One B-rep face of a CAD part: STEP entity #1865.
In plain terms, the planar face has unit normal (1, 0, 0).
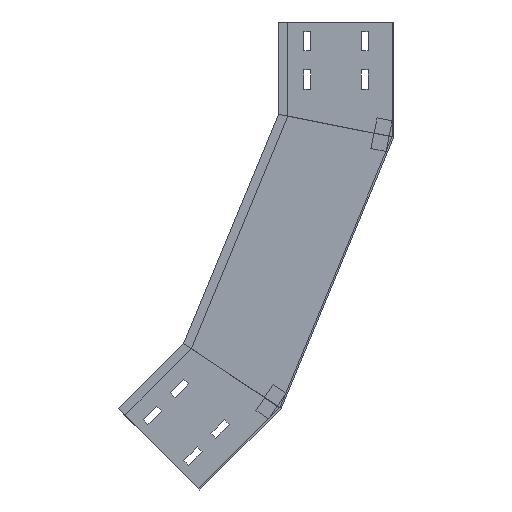
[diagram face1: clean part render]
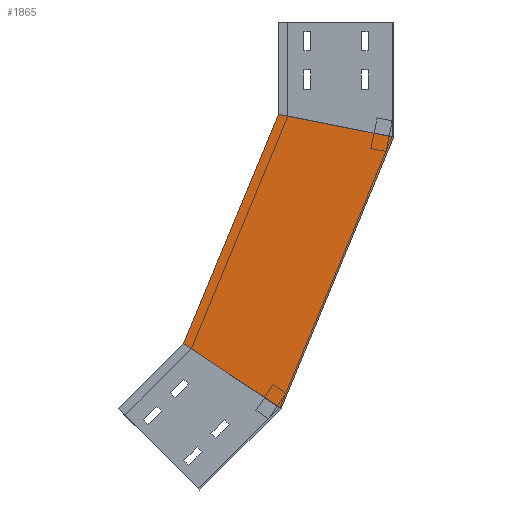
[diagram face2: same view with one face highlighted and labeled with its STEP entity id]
Its self-contained STEP definition (entity closure, numbers rounded to 3 decimals):
#6 = VERTEX_POINT ( 'NONE', #1613 ) ;
#12 = VECTOR ( 'NONE', #348, 1000. ) ;
#15 = CARTESIAN_POINT ( 'NONE',  ( 0., 138.582, -92.597 ) ) ;
#156 = ORIENTED_EDGE ( 'NONE', *, *, #1581, .T. ) ;
#183 = DIRECTION ( 'NONE',  ( 0., 0.383, -0.924 ) ) ;
#269 = ORIENTED_EDGE ( 'NONE', *, *, #1546, .F. ) ;
#299 = DIRECTION ( 'NONE',  ( 0., 0.383, -0.924 ) ) ;
#302 = VECTOR ( 'NONE', #299, 1000. ) ;
#332 = EDGE_CURVE ( 'NONE', #1325, #1732, #335, .T. ) ;
#335 = LINE ( 'NONE', #1599, #1404 ) ;
#348 = DIRECTION ( 'NONE',  ( 0., -0.831, -0.556 ) ) ;
#407 = CARTESIAN_POINT ( 'NONE',  ( 0., 146.568, -503.846 ) ) ;
#596 = PLANE ( 'NONE',  #770 ) ;
#711 = ORIENTED_EDGE ( 'NONE', *, *, #1986, .F. ) ;
#759 = EDGE_LOOP ( 'NONE', ( #711, #156, #1067, #269 ) ) ;
#768 = DIRECTION ( 'NONE',  ( -1., 0., 0. ) ) ;
#770 = AXIS2_PLACEMENT_3D ( 'NONE', #1549, #768, #1187 ) ;
#823 = LINE ( 'NONE', #832, #1818 ) ;
#832 = CARTESIAN_POINT ( 'NONE',  ( 0., 28.701, -144.291 ) ) ;
#1067 = ORIENTED_EDGE ( 'NONE', *, *, #332, .T. ) ;
#1081 = LINE ( 'NONE', #15, #302 ) ;
#1187 = DIRECTION ( 'NONE',  ( 0., 0., 1. ) ) ;
#1323 = CARTESIAN_POINT ( 'NONE',  ( 0., 0., -150. ) ) ;
#1325 = VERTEX_POINT ( 'NONE', #1323 ) ;
#1402 = CARTESIAN_POINT ( 'NONE',  ( 0., 150., -120.163 ) ) ;
#1404 = VECTOR ( 'NONE', #183, 1000. ) ;
#1442 = VERTEX_POINT ( 'NONE', #1402 ) ;
#1546 = EDGE_CURVE ( 'NONE', #6, #1732, #1730, .T. ) ;
#1549 = CARTESIAN_POINT ( 'NONE',  ( 0., 0., -150. ) ) ;
#1573 = CARTESIAN_POINT ( 'NONE',  ( 0., 208.695, -462.334 ) ) ;
#1581 = EDGE_CURVE ( 'NONE', #1442, #1325, #823, .T. ) ;
#1599 = CARTESIAN_POINT ( 'NONE',  ( 0., 0., -150. ) ) ;
#1613 = CARTESIAN_POINT ( 'NONE',  ( 0., 273.732, -418.878 ) ) ;
#1730 = LINE ( 'NONE', #1573, #12 ) ;
#1732 = VERTEX_POINT ( 'NONE', #407 ) ;
#1818 = VECTOR ( 'NONE', #1923, 1000. ) ;
#1865 = ADVANCED_FACE ( 'NONE', ( #1874 ), #596, .F. ) ;
#1874 = FACE_OUTER_BOUND ( 'NONE', #759, .T. ) ;
#1923 = DIRECTION ( 'NONE',  ( 0., -0.981, -0.195 ) ) ;
#1986 = EDGE_CURVE ( 'NONE', #1442, #6, #1081, .T. ) ;
